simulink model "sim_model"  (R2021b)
settings: Solver=ode45  StartTime=0.0  StopTime=timeend_sim  RelTol=1e-3  EnableMultiTasking=on
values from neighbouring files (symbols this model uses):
  sel_att = 2    [runsim_sysid.m]    (also in sim_param.m = 1)
  sel_attrate = 1    [runsim_sysid.m]    (also in sim_param.m)
  sel_dltx = 1    [runsim_sysid.m]    (also in sim_param.m; runsim_ct.m = 3)
  sel_motor_thr = 1    [runsim_sysid.m]    (also in sim_param.m)
  sel_pos = 2    [runsim_sysid.m]    (also in sim_param.m = 1)
  sel_qtcalc = 1    [sim_param.m]
  sel_vel = 2    [runsim_sysid.m]    (also in sim_param.m = 1)
  sel_x_s1 = 2    [runsim_sysid.m]    (also in sim_param.m = 1)
  sel_y_s1 = 2    [runsim_sysid.m]    (also in sim_param.m = 1)
  sel_z_s1 = 2    [runsim_sysid.m]    (also in sim_param.m = 1)
undefined symbols (not defined in the file or in its folder): ct, ct2, DiscIntNeverNeededParam, mdl
libraries: simulink x4

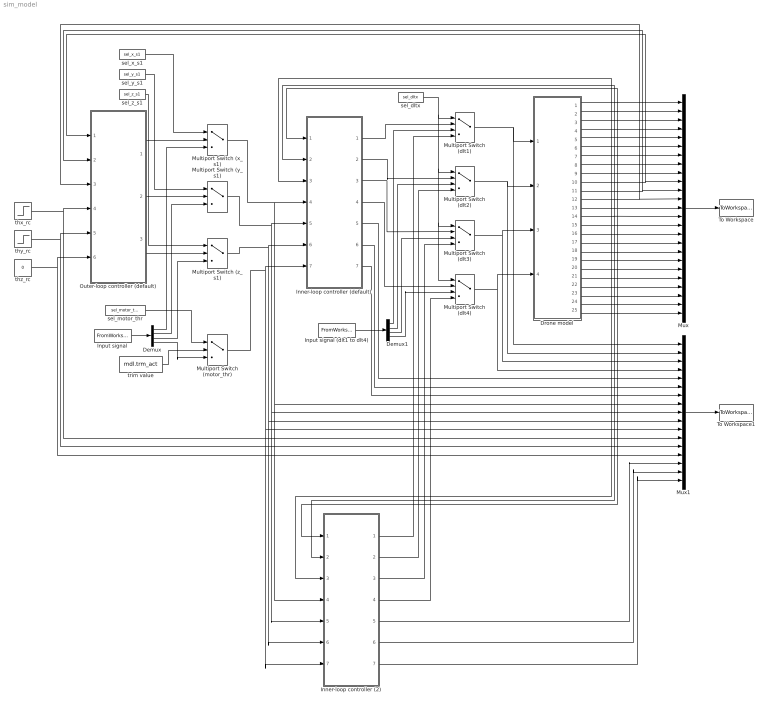
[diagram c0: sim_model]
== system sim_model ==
  Demux : Demux
  Demux1 : Demux
  Drone model : Subsystem
  Inner-loop controller (2) : Subsystem  TreatAsAtomicUnit=on  SystemSampleTime=ct2.ts_ctrl_i
  Inner-loop controller (default) : Subsystem  TreatAsAtomicUnit=on  SystemSampleTime=ct.ts_ctrl_i
  Input signal : FromWorkspace  VariableName=u_in
  Input signal (dlt1 to dlt4) : FromWorkspace  VariableName=dltx_in
  Multiport Switch (dlt1) : MultiPortSwitch
  Multiport Switch (dlt2) : MultiPortSwitch
  Multiport Switch (dlt3) : MultiPortSwitch
  Multiport Switch (dlt4) : MultiPortSwitch
  Multiport Switch (motor_thr) : MultiPortSwitch  Inputs=2
  Multiport Switch (x_s1) : MultiPortSwitch  Inputs=2
  Multiport Switch (y_s1) : MultiPortSwitch  Inputs=2
  Multiport Switch (z_s1) : MultiPortSwitch  Inputs=2
  Mux : Mux  Inputs=25
  Mux1 : Mux  Inputs=17
  Outer-loop controller (default) : Subsystem  TreatAsAtomicUnit=on  SystemSampleTime=ct.ts_ctrl_o
  To Workspace : ToWorkspace  VariableName=state_out  SaveFormat=Structure With Time  SampleTime=ct.ts_ctrl_i
  To Workspace1 : ToWorkspace  VariableName=ctrl_out  SaveFormat=Structure With Time  SampleTime=ct.ts_ctrl_i
  sel_dltx : Constant  Value=sel_dltx
  sel_motor_thr : Constant  Value=sel_motor_thr
  sel_x_s1 : Constant  Value=sel_x_s1
  sel_y_s1 : Constant  Value=sel_y_s1
  sel_z_s1 : Constant  Value=sel_z_s1
  thx_rc : Step  After=0.2  SampleTime=0
  thy_rc : Step  Time=3  After=-0.2  SampleTime=0
  thz_rc : Constant  Value=0
  trim value : Constant  Value=mdl.trm_act
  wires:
  Drone model/15(gz) -> Inner-loop controller (2)/3(gz), Mux/15, Inner-loop controller (default)/3(gz)
  Drone model/14(gy) -> Inner-loop controller (2)/2(gy), Mux/14, Inner-loop controller (default)/2(gy)
  Drone model/13(gx) -> Inner-loop controller (2)/1(gx), Mux/13, Inner-loop controller (default)/1(gx)
  Drone model/12(thz) -> Mux/12, Outer-loop controller (default)/3(thz_ahrs)
  Drone model/11(thy) -> Mux/11, Outer-loop controller (default)/2(thy_ahrs)
  Drone model/10(thx) -> Mux/10, Outer-loop controller (default)/1(thx_ahrs)
  thx_rc/1 -> Mux1/12, Outer-loop controller (default)/4(thx_rc)
  thy_rc/1 -> Mux1/13, Outer-loop controller (default)/5(thy_rc)
  thz_rc/1 -> Mux1/14, Outer-loop controller (default)/6(thz_rc)
  Mux/1 -> To Workspace/1
  Drone model/1(PXN) -> Mux/1
  Drone model/2(PYN) -> Mux/2
  Drone model/3(PZN) -> Mux/3
  Drone model/4(VXB) -> Mux/4
  Drone model/5(VYB) -> Mux/5
  Drone model/6(VZB) -> Mux/6
  Drone model/7(VXBdot) -> Mux/7
  Drone model/8(VYBdot) -> Mux/8
  Drone model/9(VZBdot) -> Mux/9
  Drone model/21(az) -> Mux/21
  Drone model/16(gxdot) -> Mux/16
  Drone model/17(gydot) -> Mux/17
  Drone model/18(gzdot) -> Mux/18
  Drone model/19(ax) -> Mux/19
  Drone model/20(ay) -> Mux/20
  Multiport Switch (x_s1)/1 -> Inner-loop controller (default)/4(x_s1), Inner-loop controller (2)/4(x_s1), Mux1/8
  Multiport Switch (y_s1)/1 -> Inner-loop controller (default)/5(y_s1), Inner-loop controller (2)/5(y_s1), Mux1/9
  Multiport Switch (z_s1)/1 -> Inner-loop controller (default)/6(z_s1), Inner-loop controller (2)/6(z_s1), Mux1/10
  Input signal/1 -> Demux/1
  Multiport Switch (motor_thr)/1 -> Inner-loop controller (default)/7(motor_thr), Inner-loop controller (2)/7(motor_thr), Mux1/11
  Drone model/22(Za) -> Mux/22
  Drone model/23(La) -> Mux/23
  Drone model/24(Ma) -> Mux/24
  Drone model/25(Na) -> Mux/25
  Multiport Switch (dlt1)/1 -> Drone model/1(dlt1), Mux1/1
  Multiport Switch (dlt2)/1 -> Drone model/2(dlt2), Mux1/2
  Multiport Switch (dlt3)/1 -> Drone model/3(dlt3), Mux1/3
  Multiport Switch (dlt4)/1 -> Drone model/4(dlt4), Mux1/4
  sel_dltx/1 -> Multiport Switch (dlt1)/1, Multiport Switch (dlt2)/1, Multiport Switch (dlt3)/1, Multiport Switch (dlt4)/1
  Mux1/1 -> To Workspace1/1
  Inner-loop controller (default)/4(motor4_pwm) -> Multiport Switch (dlt4)/2
  Input signal (dlt1 to dlt4)/1 -> Demux1/1
  Demux1/4 -> Multiport Switch (dlt4)/3
  Demux1/3 -> Multiport Switch (dlt3)/3
  Demux1/2 -> Multiport Switch (dlt2)/3
  Demux1/1 -> Multiport Switch (dlt1)/3
  Inner-loop controller (default)/1(motor1_pwm) -> Multiport Switch (dlt1)/2
  Inner-loop controller (default)/2(motor2_pwm) -> Multiport Switch (dlt2)/2
  Inner-loop controller (default)/3(motor3_pwm) -> Multiport Switch (dlt3)/2
  Inner-loop controller (2)/1(motor1_pwm) -> Multiport Switch (dlt1)/4
  Inner-loop controller (2)/2(motor2_pwm) -> Multiport Switch (dlt2)/4
  Inner-loop controller (2)/3(motor3_pwm) -> Multiport Switch (dlt3)/4
  Inner-loop controller (2)/4(motor4_pwm) -> Multiport Switch (dlt4)/4
  sel_x_s1/1 -> Multiport Switch (x_s1)/1
  sel_y_s1/1 -> Multiport Switch (y_s1)/1
  sel_z_s1/1 -> Multiport Switch (z_s1)/1
  Outer-loop controller (default)/1(x_s1) -> Multiport Switch (x_s1)/2
  Outer-loop controller (default)/2(y_s1) -> Multiport Switch (y_s1)/2
  Outer-loop controller (default)/3(z_s1) -> Multiport Switch (z_s1)/2
  Demux/1 -> Multiport Switch (x_s1)/3
  Demux/2 -> Multiport Switch (y_s1)/3
  Demux/3 -> Multiport Switch (z_s1)/3
  sel_motor_thr/1 -> Multiport Switch (motor_thr)/1
  trim value/1 -> Multiport Switch (motor_thr)/2
  Demux/4 -> Multiport Switch (motor_thr)/3
  Inner-loop controller (default)/7(z_s2) -> Mux1/7
  Inner-loop controller (default)/6(y_s2) -> Mux1/6
  Inner-loop controller (default)/5(x_s2) -> Mux1/5
  Inner-loop controller (2)/5(x_s2) -> Mux1/15
  Inner-loop controller (2)/6(y_s2) -> Mux1/16
  Inner-loop controller (2)/7(z_s2) -> Mux1/17

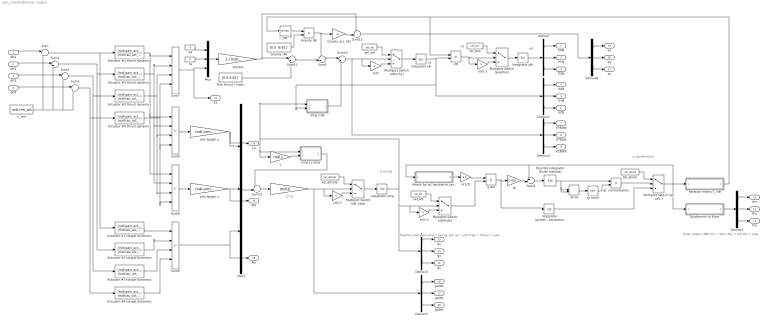
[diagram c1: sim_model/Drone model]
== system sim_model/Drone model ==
  note: Angular velocities omg = [gx gy gz]' gx = pitch gy = roll gz = yaw
  note: vN
  note: pN
  note: Euler angles (NB) thx = pitch thy = roll thz = yaw
  note: q (quaternion)
  note: vB
  note: ω (omg)
  dlt1 : Inport  PortDimensions=1
  dlt2 : Inport  Port=2  PortDimensions=1
  dlt3 : Inport  Port=3  PortDimensions=1
  dlt4 : Inport  Port=4  PortDimensions=1
  1/mass : Gain  Gain=1 / mdl.mtotal
  Actuator #1 thrust dynamics : TransferFcn  Numerator=[mdl.gain_act_t]  Denominator=[mdl.tau_act_t 1]
  Actuator #1 torque dynamics : TransferFcn  Numerator=[mdl.gain_act_r]  Denominator=[mdl.tau_act_r 1]
  Actuator #2 thrust dynamics : TransferFcn  Numerator=[mdl.gain_act_t]  Denominator=[mdl.tau_act_t 1]
  Actuator #2 torque dynamics : TransferFcn  Numerator=[mdl.gain_act_r]  Denominator=[mdl.tau_act_r 1]
  Actuator #3 thrust dynamics : TransferFcn  Numerator=[mdl.gain_act_t]  Denominator=[mdl.tau_act_t 1]
  Actuator #3 torque dynamics : TransferFcn  Numerator=[mdl.gain_act_r]  Denominator=[mdl.tau_act_r 1]
  Actuator #4 thrust dynamics : TransferFcn  Numerator=[mdl.gain_act_t]  Denominator=[mdl.tau_act_t 1]
  Actuator #4 torque dynamics : TransferFcn  Numerator=[mdl.gain_act_r]  Denominator=[mdl.tau_act_r 1]
  C_NB^T : Math  Operator=transpose  SignedPower=on
  Demux{,1..6} (7 alike) : Demux  Outputs=3
  Discrete integrator (Euler method) : UnitDelay  InitialCondition=[1 0 0 0]'  SampleTime=0.001
  Gravity (B) : Product  Multiplication=Matrix(*)  RndMeth=Zero
  Gravity (N) : Constant  Value=[0 0 -9.81]'
  Gravity acc. (B) : Gain  Gain=-1
  Integrator (quaternion) for linearization : Integrator  InitialCondition=[1 0 0 0]'
  Integrator omg : Integrator  InitialCondition=[0 0 0]'
  Integrator pN : Integrator  InitialCondition=[0 0 0]'
  Integrator vB : Integrator  InitialCondition=[0 0 0]'
  J : Gain  Gain=mdl.J  Multiplication=Matrix(K*u)
  J^-1 : Gain  Gain=mdl.Ji  Multiplication=Matrix(K*u)
  Matrix for qt. derivative calc. : Subsystem
  Multiport Switch (att. rate) : MultiPortSwitch  Inputs=2
  Multiport Switch (attitude) : MultiPortSwitch  Inputs=2
  Multiport Switch (position) : MultiPortSwitch  Inputs=2
  Multiport Switch (qt. calc.) : MultiPortSwitch  Inputs=2
  Multiport Switch (velocity) : MultiPortSwitch  Inputs=2
  Mux : Mux  Inputs=3
  Mux1 : Mux  Inputs=3
  Quaternion to Euler : Subsystem
  Rotation matrix C_NB : Subsystem
  Sum{,1..3,10} (5 alike) : Sum  Inputs=|+-
  Sum11 : Sum  Inputs=|++
  Sum12 : Sum  Inputs=++|
  Sum13 : Sum  Inputs=-+|
  Sum4 : Sum  Inputs=++|
  Sum5 : Sum  Inputs=++|
  Sum6 : Sum  Inputs=+-+-
  Sum7 : Sum  Inputs=4
  Sum8 : Sum  Inputs=-++-
  Sum9 : Sum  Inputs=--++
  Trim thrust / mass : Constant  Value=[0 0 9.81]'
  Xa : Constant  Value=0
  Ya : Constant  Value=0
  arm length x : Gain  Gain=mdl.armlenxx
  arm length y : Gain  Gain=mdl.armlenyy
  dt : Gain  Gain=0.001
  omg x J omg : Subsystem
  omg x vB : Subsystem
  q-dot : Product  Multiplication=Matrix(*)  RndMeth=Zero
  qt norm : Sqrt
  qt sq : DotProduct
  qt. normalization : Product  Inputs=*/  RndMeth=Zero
  sel_att : Constant  Value=sel_att
  sel_attrate : Constant  Value=sel_attrate
  sel_pos : Constant  Value=sel_pos
  sel_qtcalc : Constant  Value=sel_qtcalc
  sel_vel : Constant  Value=sel_vel
  u_trm : Constant  Value=mdl.trm_act
  vN : Product  Multiplication=Matrix(*)  RndMeth=Zero
  x(0) : Gain  Gain=0
  x(0) 1 : Gain  Gain=0
  x(0) 2 : Gain  Gain=0
  x(0) 3 : Gain  Gain=0
  x(1/2) : Gain  Gain=0.5
  PXN : Outport
  PYN : Outport  Port=2
  PZN : Outport  Port=3
  VXB : Outport  Port=4
  VYB : Outport  Port=5
  VZB : Outport  Port=6
  VXBdot : Outport  Port=7
  VYBdot : Outport  Port=8
  VZBdot : Outport  Port=9
  thx : Outport  Port=10
  thy : Outport  Port=11
  thz : Outport  Port=12
  gx : Outport  Port=13
  gy : Outport  Port=14
  gz : Outport  Port=15
  gxdot : Outport  Port=16
  gydot : Outport  Port=17
  gzdot : Outport  Port=18
  ax : Outport  Port=19
  ay : Outport  Port=20
  az : Outport  Port=21
  Za : Outport  Port=22
  La : Outport  Port=23
  Ma : Outport  Port=24
  Na : Outport  Port=25
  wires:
  dlt1/1 -> Sum/1
  Sum/1 -> Actuator #1 thrust dynamics/1, Actuator #1 torque dynamics/1
  dlt2/1 -> Sum1/1
  dlt3/1 -> Sum2/1
  dlt4/1 -> Sum3/1
  Sum3/1 -> Actuator #4 thrust dynamics/1, Actuator #4 torque dynamics/1
  u_trm/1 -> Sum/2, Sum1/2, Sum2/2, Sum3/2
  Actuator #1 thrust dynamics/1 -> Sum7/1, Sum8/1, Sum9/1
  Actuator #2 thrust dynamics/1 -> Sum7/2, Sum8/2, Sum9/2
  Actuator #3 thrust dynamics/1 -> Sum7/3, Sum8/3, Sum9/3
  Actuator #4 thrust dynamics/1 -> Sum7/4, Sum8/4, Sum9/4
  Sum1/1 -> Actuator #2 thrust dynamics/1, Actuator #2 torque dynamics/1
  Sum2/1 -> Actuator #3 thrust dynamics/1, Actuator #3 torque dynamics/1
  Sum9/1 -> arm length x/1
  Sum8/1 -> arm length y/1
  Actuator #1 torque dynamics/1 -> Sum6/1
  Actuator #2 torque dynamics/1 -> Sum6/2
  Actuator #3 torque dynamics/1 -> Sum6/3
  Actuator #4 torque dynamics/1 -> Sum6/4
  Sum6/1 -> Na/1, Mux1/3
  1/mass/1 -> Sum11/1, Sum12/1
  Sum10/1 -> x(0)/1, Multiport Switch (velocity)/2, Demux4/1
  Integrator vB/1 -> vN/2, omg x vB/2(U2), Demux1/1
  Mux/1 -> 1/mass/1
  Xa/1 -> Mux/1
  Ya/1 -> Mux/2
  Sum7/1 -> Mux/3, Za/1
  arm length y/1 -> Mux1/1, La/1
  arm length x/1 -> Mux1/2, Ma/1
  Gravity (N)/1 -> Gravity (B)/2
  C_NB^T/1 -> Gravity (B)/1
  Sum5/1 -> Sum10/1
  Gravity (B)/1 -> Sum5/1, Gravity acc. (B)/1
  Trim thrust / mass/1 -> Sum11/2
  Sum11/1 -> Sum5/2
  Rotation matrix C_NB/1(Rotation mat.) -> C_NB^T/1, vN/1
  Integrator pN/1 -> Demux/1
  Demux/1 -> PXN/1
  Demux/2 -> PYN/1
  Demux/3 -> PZN/1
  Demux1/1 -> VXB/1
  Demux1/2 -> VYB/1
  Demux1/3 -> VZB/1
  Demux2/1 -> thx/1
  Demux2/2 -> thy/1
  Demux2/3 -> thz/1
  Demux3/2 -> gy/1
  Demux3/3 -> gz/1
  Matrix for qt. derivative calc./1(q-times-(omg)) -> x(1/2)/1
  x(1/2)/1 -> q-dot/1
  Quaternion to Euler/1(Euler angles) -> Demux2/1
  Discrete integrator (Euler method)/1 -> qt sq/1, qt sq/2, qt. normalization/1
  qt sq/1 -> qt norm/1
  qt norm/1 -> qt. normalization/2
  Multiport Switch (qt. calc.)/1 -> Quaternion to Euler/1(Quaternion), Rotation matrix C_NB/1(Quaternion), Matrix for qt. derivative calc./1(Quaternion), Sum4/1
  Sum4/1 -> Discrete integrator (Euler method)/1
  dt/1 -> Sum4/2
  q-dot/1 -> Integrator (quaternion) for linearization/1, dt/1
  Demux4/1 -> VXBdot/1
  Demux4/2 -> VYBdot/1
  Demux4/3 -> VZBdot/1
  Demux5/1 -> gxdot/1
  Demux5/2 -> gydot/1
  Demux5/3 -> gzdot/1
  Gravity acc. (B)/1 -> Sum12/2
  Sum12/1 -> Demux6/1
  Demux6/1 -> ax/1
  Demux6/2 -> ay/1
  Demux6/3 -> az/1
  qt. normalization/1 -> Multiport Switch (qt. calc.)/2
  Integrator (quaternion) for linearization/1 -> Multiport Switch (qt. calc.)/3
  omg x vB/1(U1 x U2) -> Sum10/2
  Demux3/1 -> gx/1
  Multiport Switch (velocity)/1 -> Integrator vB/1
  sel_vel/1 -> Multiport Switch (velocity)/1
  x(0)/1 -> Multiport Switch (velocity)/3
  sel_pos/1 -> Multiport Switch (position)/1
  Multiport Switch (position)/1 -> Integrator pN/1
  vN/1 -> x(0) 1/1, Multiport Switch (position)/2
  x(0) 1/1 -> Multiport Switch (position)/3
  sel_attrate/1 -> Multiport Switch (att. rate)/1
  J^-1/1 -> x(0) 2/1, Multiport Switch (att. rate)/2, Demux5/1
  x(0) 2/1 -> Multiport Switch (att. rate)/3
  Multiport Switch (att. rate)/1 -> Integrator omg/1
  sel_att/1 -> Multiport Switch (attitude)/1
  Integrator omg/1 -> x(0) 3/1, Multiport Switch (attitude)/2, Demux3/1, J/1, omg x J omg/1(U1), omg x vB/1(U1)
  x(0) 3/1 -> Multiport Switch (attitude)/3
  Multiport Switch (attitude)/1 -> q-dot/2
  sel_qtcalc/1 -> Multiport Switch (qt. calc.)/1
  J/1 -> omg x J omg/2(U2)
  Sum13/1 -> J^-1/1
  Mux1/1 -> Sum13/2
  omg x J omg/1(U1 x U2) -> Sum13/1

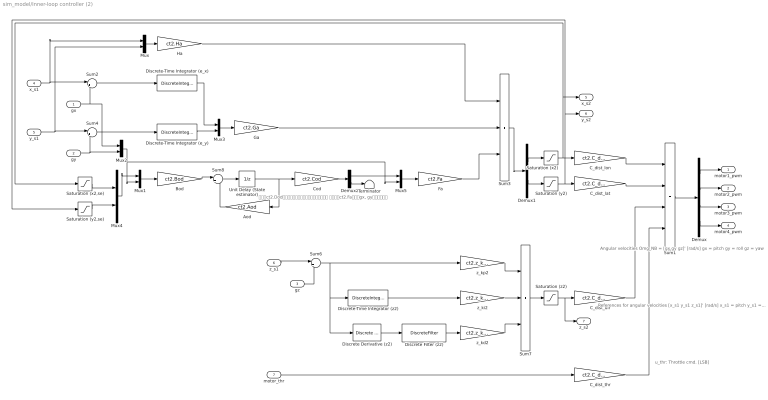
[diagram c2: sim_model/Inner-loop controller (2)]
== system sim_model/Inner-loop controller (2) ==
  note: u_thr: Throttle cmd. [LSB]
  note: References for angular velocities [x_s1 y_s1 z_s1]' [rad/s] x_s1 = pitch y_s1 = roll z_s1 = yaw
  note: Angular velocities Omg_NB = [gx gy gz]' [rad/s] gx = pitch gy = roll gz = yaw
  note: 注意：ct2.Dodを使うと代数ループの警告が出るので、 代わりにct2.Faへ直接gx, gyを入力する。
  gx : Inport  PortDimensions=1
  gy : Inport  Port=2  PortDimensions=1
  gz : Inport  Port=3  PortDimensions=1
  x_s1 : Inport  Port=4  PortDimensions=1
  y_s1 : Inport  Port=5  PortDimensions=1
  z_s1 : Inport  Port=6  PortDimensions=1
  motor_thr : Inport  Port=7  PortDimensions=1
  Aod : Gain  Gain=ct2.Aod  Multiplication=Matrix(K*u)
  Bod : Gain  Gain=ct2.Bod  Multiplication=Matrix(K*u)
  C_dist_dir : Gain  Gain=ct2.C_dist_dir  Multiplication=Matrix(K*u)
  C_dist_lat : Gain  Gain=ct2.C_dist_lat  Multiplication=Matrix(K*u)
  C_dist_lon : Gain  Gain=ct2.C_dist_lon  Multiplication=Matrix(K*u)
  C_dist_thr : Gain  Gain=ct2.C_dist_thr  Multiplication=Matrix(K*u)
  Cod : Gain  Gain=ct2.Cod  Multiplication=Matrix(K*u)
  Demux : Demux
  Demux1 : Demux  Outputs=2
  Demux2 : Demux  Outputs=[2 2]
  Discrete Derivative (z2) : simulink/Discrete/Discrete Derivative  gainval=1.0  ICPrevScaledInput=0.0  OutMin=[]  OutMax=[]  OutDataType=sfix(16)  OutScaling=2^-10  DoSatur=off
  Discrete Filter (z2) : DiscreteFilter  Numerator=[ct2.coef_dflt 0]  Denominator=[1 (ct2.coef_dflt - 1)]
  Discrete-Time Integrator (e_x) : DiscreteIntegrator  SampleTime=-1  LimitOutput=on  UpperSaturationLimit=20  LowerSaturationLimit=-20  ICPrevOutput=DiscIntNeverNeededParam  ICPrevScaledInput=DiscIntNeverNeededParam
  Discrete-Time Integrator (e_y) : DiscreteIntegrator  SampleTime=-1  LimitOutput=on  UpperSaturationLimit=20  LowerSaturationLimit=-20  ICPrevOutput=DiscIntNeverNeededParam  ICPrevScaledInput=DiscIntNeverNeededParam
  Discrete-Time Integrator (z2) : DiscreteIntegrator  SampleTime=-1  LimitOutput=on  UpperSaturationLimit=2  LowerSaturationLimit=-2  ICPrevOutput=DiscIntNeverNeededParam  ICPrevScaledInput=DiscIntNeverNeededParam
  Fa : Gain  Gain=ct2.Fa  Multiplication=Matrix(K*u)
  Ga : Gain  Gain=ct2.Ga  Multiplication=Matrix(K*u)
  Ha : Gain  Gain=ct2.Ha  Multiplication=Matrix(K*u)
  Mux{,1..5} (6 alike) : Mux  Inputs=2
  Saturation (x2) : Saturate  UpperLimit=800  LowerLimit=-800
  Saturation (x2,se) : Saturate  UpperLimit=60  LowerLimit=-60
  Saturation (y2) : Saturate  UpperLimit=800  LowerLimit=-800
  Saturation (y2,se) : Saturate  UpperLimit=60  LowerLimit=-60
  Saturation (z2) : Saturate  UpperLimit=800  LowerLimit=-800
  Sum1 : Sum  Inputs=4
  Sum2 : Sum  Inputs=|+-
  Sum3 : Sum  Inputs=3
  Sum4 : Sum  Inputs=|+-
  Sum6 : Sum  Inputs=|+-
  Sum7 : Sum  Inputs=3
  Sum8 : Sum  Inputs=|++
  Terminator : Terminator
  Unit Delay (State estimator) : UnitDelay  SampleTime=-1
  z_kd2 : Gain  Gain=ct2.z_kd2
  z_ki2 : Gain  Gain=ct2.z_ki2
  z_kp2 : Gain  Gain=ct2.z_kp2
  motor1_pwm : Outport
  motor2_pwm : Outport  Port=2
  motor3_pwm : Outport  Port=3
  motor4_pwm : Outport  Port=4
  x_s2 : Outport  Port=5
  y_s2 : Outport  Port=6
  z_s2 : Outport  Port=7
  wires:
  C_dist_thr/1 -> Sum1/4
  motor_thr/1 -> C_dist_thr/1
  Demux/4 -> motor4_pwm/1
  Demux/3 -> motor3_pwm/1
  Demux/2 -> motor2_pwm/1
  Demux/1 -> motor1_pwm/1
  Sum1/1 -> Demux/1
  C_dist_dir/1 -> Sum1/3
  gz/1 -> Sum6/2
  Discrete Derivative (z2)/1 -> Discrete Filter (z2)/1
  Sum6/1 -> z_kp2/1, Discrete-Time Integrator (z2)/1, Discrete Derivative (z2)/1
  z_s1/1 -> Sum6/1
  C_dist_lon/1 -> Sum1/1
  gx/1 -> Sum2/2, Mux2/1
  x_s1/1 -> Sum2/1, Mux/1
  C_dist_lat/1 -> Sum1/2
  gy/1 -> Sum4/2, Mux2/2
  y_s1/1 -> Sum4/1, Mux/2
  Mux/1 -> Ha/1
  Unit Delay (State estimator)/1 -> Cod/1, Aod/1
  Sum8/1 -> Unit Delay (State estimator)/1
  Aod/1 -> Sum8/2
  Sum2/1 -> Discrete-Time Integrator (e_x)/1
  Sum4/1 -> Discrete-Time Integrator (e_y)/1
  Discrete-Time Integrator (e_x)/1 -> Mux3/1
  Discrete-Time Integrator (e_y)/1 -> Mux3/2
  Mux3/1 -> Ga/1
  Fa/1 -> Sum3/3
  Ga/1 -> Sum3/2
  Ha/1 -> Sum3/1
  Sum3/1 -> Demux1/1
  Bod/1 -> Sum8/1
  Demux1/2 -> Saturation (y2)/1
  Saturation (y2)/1 -> C_dist_lat/1, Saturation (y2,se)/1, y_s2/1
  Sum7/1 -> Saturation (z2)/1
  Saturation (z2)/1 -> z_s2/1, C_dist_dir/1
  Saturation (x2)/1 -> C_dist_lon/1, Saturation (x2,se)/1, x_s2/1
  Demux1/1 -> Saturation (x2)/1
  z_kp2/1 -> Sum7/1
  z_ki2/1 -> Sum7/2
  z_kd2/1 -> Sum7/3
  Discrete-Time Integrator (z2)/1 -> z_ki2/1
  Discrete Filter (z2)/1 -> z_kd2/1
  Mux1/1 -> Bod/1
  Cod/1 -> Demux2/1
  Mux5/1 -> Fa/1
  Demux2/2 -> Terminator/1
  Demux2/1 -> Mux5/1
  Mux2/1 -> Mux5/2, Mux1/2
  Saturation (x2,se)/1 -> Mux4/1
  Saturation (y2,se)/1 -> Mux4/2
  Mux4/1 -> Mux1/1

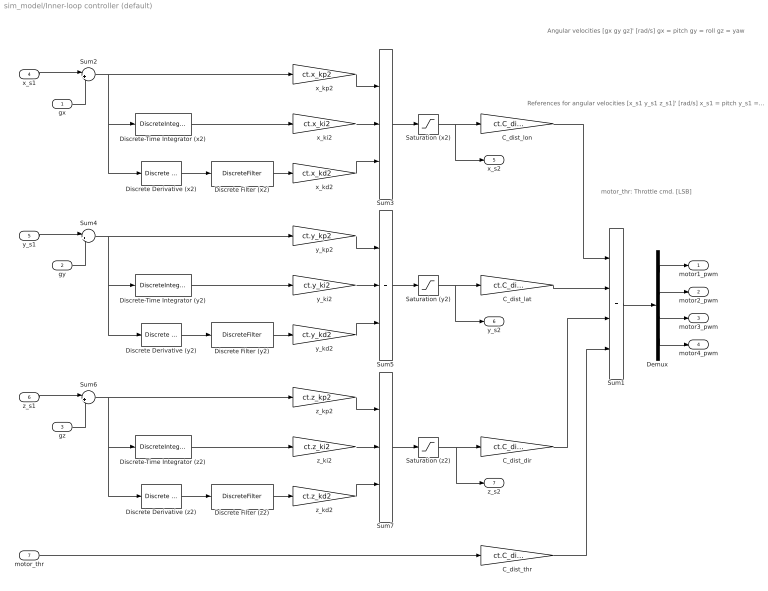
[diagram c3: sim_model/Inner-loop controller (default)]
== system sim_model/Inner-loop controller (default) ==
  note: Angular velocities [gx gy gz]' [rad/s] gx = pitch gy = roll gz = yaw
  note: References for angular velocities [x_s1 y_s1 z_s1]' [rad/s] x_s1 = pitch y_s1 = roll z_s1 = yaw
  note: motor_thr: Throttle cmd. [LSB]
  gx : Inport  PortDimensions=1
  gy : Inport  Port=2  PortDimensions=1
  gz : Inport  Port=3  PortDimensions=1
  x_s1 : Inport  Port=4  PortDimensions=1
  y_s1 : Inport  Port=5  PortDimensions=1
  z_s1 : Inport  Port=6  PortDimensions=1
  motor_thr : Inport  Port=7  PortDimensions=1
  C_dist_dir : Gain  Gain=ct.C_dist_dir  Multiplication=Matrix(K*u)
  C_dist_lat : Gain  Gain=ct.C_dist_lat  Multiplication=Matrix(K*u)
  C_dist_lon : Gain  Gain=ct.C_dist_lon  Multiplication=Matrix(K*u)
  C_dist_thr : Gain  Gain=ct.C_dist_thr  Multiplication=Matrix(K*u)
  Demux : Demux
  Discrete Derivative (x2) : simulink/Discrete/Discrete Derivative  gainval=1.0  ICPrevScaledInput=0.0  OutMin=[]  OutMax=[]  OutDataType=sfix(16)  OutScaling=2^-10  DoSatur=off
  Discrete Derivative (y2) : simulink/Discrete/Discrete Derivative  gainval=1.0  ICPrevScaledInput=0.0  OutMin=[]  OutMax=[]  OutDataType=sfix(16)  OutScaling=2^-10  DoSatur=off
  Discrete Derivative (z2) : simulink/Discrete/Discrete Derivative  gainval=1.0  ICPrevScaledInput=0.0  OutMin=[]  OutMax=[]  OutDataType=sfix(16)  OutScaling=2^-10  DoSatur=off
  Discrete Filter (x2) : DiscreteFilter  Numerator=[ct.coef_dflt 0]  Denominator=[1 (ct.coef_dflt - 1)]
  Discrete Filter (y2) : DiscreteFilter  Numerator=[ct.coef_dflt 0]  Denominator=[1 (ct.coef_dflt - 1)]
  Discrete Filter (z2) : DiscreteFilter  Numerator=[ct.coef_dflt 0]  Denominator=[1 (ct.coef_dflt - 1)]
  Discrete-Time Integrator (x2) : DiscreteIntegrator  SampleTime=-1  LimitOutput=on  UpperSaturationLimit=20  LowerSaturationLimit=-20  ICPrevOutput=DiscIntNeverNeededParam  ICPrevScaledInput=DiscIntNeverNeededParam
  Discrete-Time Integrator (y2) : DiscreteIntegrator  SampleTime=-1  LimitOutput=on  UpperSaturationLimit=20  LowerSaturationLimit=-20  ICPrevOutput=DiscIntNeverNeededParam  ICPrevScaledInput=DiscIntNeverNeededParam
  Discrete-Time Integrator (z2) : DiscreteIntegrator  SampleTime=-1  LimitOutput=on  UpperSaturationLimit=2  LowerSaturationLimit=-2  ICPrevOutput=DiscIntNeverNeededParam  ICPrevScaledInput=DiscIntNeverNeededParam
  Saturation (x2) : Saturate  UpperLimit=800  LowerLimit=-800
  Saturation (y2) : Saturate  UpperLimit=800  LowerLimit=-800
  Saturation (z2) : Saturate  UpperLimit=800  LowerLimit=-800
  Sum1 : Sum  Inputs=4
  Sum2 : Sum  Inputs=|+-
  Sum3 : Sum  Inputs=3
  Sum4 : Sum  Inputs=|+-
  Sum5 : Sum  Inputs=3
  Sum6 : Sum  Inputs=|+-
  Sum7 : Sum  Inputs=3
  x_kd2 : Gain  Gain=ct.x_kd2
  x_ki2 : Gain  Gain=ct.x_ki2
  x_kp2 : Gain  Gain=ct.x_kp2
  y_kd2 : Gain  Gain=ct.y_kd2
  y_ki2 : Gain  Gain=ct.y_ki2
  y_kp2 : Gain  Gain=ct.y_kp2
  z_kd2 : Gain  Gain=ct.z_kd2
  z_ki2 : Gain  Gain=ct.z_ki2
  z_kp2 : Gain  Gain=ct.z_kp2
  motor1_pwm : Outport
  motor2_pwm : Outport  Port=2
  motor3_pwm : Outport  Port=3
  motor4_pwm : Outport  Port=4
  x_s2 : Outport  Port=5
  y_s2 : Outport  Port=6
  z_s2 : Outport  Port=7
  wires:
  y_s1/1 -> Sum4/1
  Sum4/1 -> y_kp2/1, Discrete-Time Integrator (y2)/1, Discrete Derivative (y2)/1
  Discrete Derivative (y2)/1 -> Discrete Filter (y2)/1
  gy/1 -> Sum4/2
  C_dist_lat/1 -> Sum1/2
  x_s1/1 -> Sum2/1
  Sum2/1 -> Discrete-Time Integrator (x2)/1, Discrete Derivative (x2)/1, x_kp2/1
  x_kp2/1 -> Sum3/1
  gx/1 -> Sum2/2
  C_dist_lon/1 -> Sum1/1
  z_s1/1 -> Sum6/1
  Sum6/1 -> Discrete-Time Integrator (z2)/1, Discrete Derivative (z2)/1, z_kp2/1
  Discrete Derivative (z2)/1 -> Discrete Filter (z2)/1
  gz/1 -> Sum6/2
  C_dist_dir/1 -> Sum1/3
  Sum1/1 -> Demux/1
  Demux/1 -> motor1_pwm/1
  Demux/2 -> motor2_pwm/1
  Demux/3 -> motor3_pwm/1
  Demux/4 -> motor4_pwm/1
  motor_thr/1 -> C_dist_thr/1
  C_dist_thr/1 -> Sum1/4
  Sum3/1 -> Saturation (x2)/1
  Saturation (x2)/1 -> C_dist_lon/1, x_s2/1
  Saturation (z2)/1 -> C_dist_dir/1, z_s2/1
  Discrete Derivative (x2)/1 -> Discrete Filter (x2)/1
  Discrete-Time Integrator (x2)/1 -> x_ki2/1
  x_ki2/1 -> Sum3/2
  Discrete Filter (x2)/1 -> x_kd2/1
  x_kd2/1 -> Sum3/3
  y_kp2/1 -> Sum5/1
  Discrete-Time Integrator (y2)/1 -> y_ki2/1
  y_ki2/1 -> Sum5/2
  Discrete Filter (y2)/1 -> y_kd2/1
  y_kd2/1 -> Sum5/3
  z_kp2/1 -> Sum7/1
  Discrete-Time Integrator (z2)/1 -> z_ki2/1
  z_ki2/1 -> Sum7/2
  Discrete Filter (z2)/1 -> z_kd2/1
  z_kd2/1 -> Sum7/3
  Sum5/1 -> Saturation (y2)/1
  Sum7/1 -> Saturation (z2)/1
  Saturation (y2)/1 -> C_dist_lat/1, y_s2/1

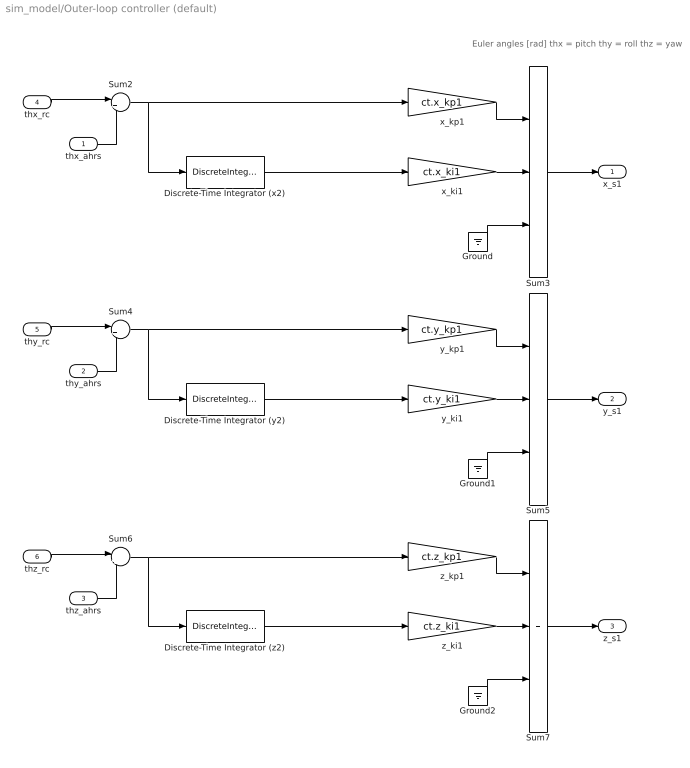
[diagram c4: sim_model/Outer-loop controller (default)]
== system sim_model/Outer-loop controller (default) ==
  note: Euler angles [rad] thx = pitch thy = roll thz = yaw
  thx_ahrs : Inport  PortDimensions=1
  thy_ahrs : Inport  Port=2  PortDimensions=1
  thz_ahrs : Inport  Port=3  PortDimensions=1
  thx_rc : Inport  Port=4  PortDimensions=1
  thy_rc : Inport  Port=5  PortDimensions=1
  thz_rc : Inport  Port=6  PortDimensions=1
  Discrete-Time Integrator (x2) : DiscreteIntegrator  SampleTime=-1  LimitOutput=on  UpperSaturationLimit=2  LowerSaturationLimit=-2  ICPrevOutput=DiscIntNeverNeededParam  ICPrevScaledInput=DiscIntNeverNeededParam
  Discrete-Time Integrator (y2) : DiscreteIntegrator  SampleTime=-1  LimitOutput=on  UpperSaturationLimit=2  LowerSaturationLimit=-2  ICPrevOutput=DiscIntNeverNeededParam  ICPrevScaledInput=DiscIntNeverNeededParam
  Discrete-Time Integrator (z2) : DiscreteIntegrator  SampleTime=-1  LimitOutput=on  UpperSaturationLimit=2  LowerSaturationLimit=-2  ICPrevOutput=DiscIntNeverNeededParam  ICPrevScaledInput=DiscIntNeverNeededParam
  Ground : Ground
  Ground1 : Ground
  Ground2 : Ground
  Sum2 : Sum  Inputs=|+-
  Sum3 : Sum  Inputs=3
  Sum4 : Sum  Inputs=|+-
  Sum5 : Sum  Inputs=3
  Sum6 : Sum  Inputs=|+-
  Sum7 : Sum  Inputs=3
  x_ki1 : Gain  Gain=ct.x_ki1
  x_kp1 : Gain  Gain=ct.x_kp1
  y_ki1 : Gain  Gain=ct.y_ki1
  y_kp1 : Gain  Gain=ct.y_kp1
  z_ki1 : Gain  Gain=ct.z_ki1
  z_kp1 : Gain  Gain=ct.z_kp1
  x_s1 : Outport
  y_s1 : Outport  Port=2
  z_s1 : Outport  Port=3
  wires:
  thz_ahrs/1 -> Sum6/2
  Ground2/1 -> Sum7/3
  z_kp1/1 -> Sum7/1
  Sum6/1 -> z_kp1/1, Discrete-Time Integrator (z2)/1
  thz_rc/1 -> Sum6/1
  thx_ahrs/1 -> Sum2/2
  x_kp1/1 -> Sum3/1
  Sum2/1 -> x_kp1/1, Discrete-Time Integrator (x2)/1
  thx_rc/1 -> Sum2/1
  thy_ahrs/1 -> Sum4/2
  Ground1/1 -> Sum5/3
  y_kp1/1 -> Sum5/1
  Sum4/1 -> y_kp1/1, Discrete-Time Integrator (y2)/1
  thy_rc/1 -> Sum4/1
  Ground/1 -> Sum3/3
  Sum5/1 -> y_s1/1
  Sum3/1 -> x_s1/1
  Sum7/1 -> z_s1/1
  Discrete-Time Integrator (x2)/1 -> x_ki1/1
  x_ki1/1 -> Sum3/2
  Discrete-Time Integrator (y2)/1 -> y_ki1/1
  y_ki1/1 -> Sum5/2
  Discrete-Time Integrator (z2)/1 -> z_ki1/1
  z_ki1/1 -> Sum7/2

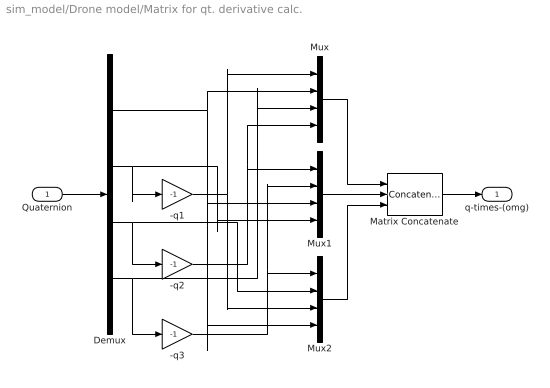
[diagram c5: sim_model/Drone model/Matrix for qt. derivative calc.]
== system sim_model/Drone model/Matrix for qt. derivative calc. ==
  Quaternion : Inport
  -q1 : Gain  Gain=-1
  -q2 : Gain  Gain=-1
  -q3 : Gain  Gain=-1
  Demux : Demux
  Matrix Concatenate : Concatenate  NumInputs=3  Mode=Multidimensional array  ConcatenateDimension=2
  Mux : Mux
  Mux1 : Mux
  Mux2 : Mux
  q-times-(omg) : Outport
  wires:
  Quaternion/1 -> Demux/1
  Demux/2 -> -q1/1, Mux1/4
  Demux/3 -> -q2/1, Mux2/2
  Demux/4 -> -q3/1, Mux/3
  -q1/1 -> Mux/1, Mux2/3
  Demux/1 -> Mux/2, Mux1/3, Mux2/4
  -q2/1 -> Mux/4, Mux1/1
  -q3/1 -> Mux1/2, Mux2/1
  Mux1/1 -> Matrix Concatenate/2
  Mux/1 -> Matrix Concatenate/1
  Mux2/1 -> Matrix Concatenate/3
  Matrix Concatenate/1 -> q-times-(omg)/1

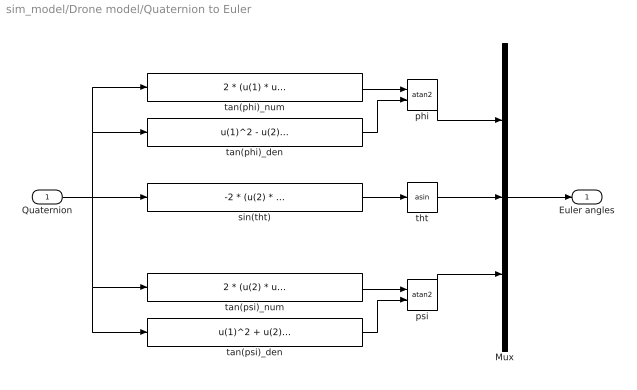
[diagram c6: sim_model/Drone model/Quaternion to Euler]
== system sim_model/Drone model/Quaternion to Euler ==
  Quaternion : Inport  PortDimensions=4
  Mux : Mux  Inputs=3
  phi : Trigonometry  Operator=atan2
  psi : Trigonometry  Operator=atan2
  sin(tht) : Fcn  Expr=-2 * (u(2) * u(4) - u(1) * u(3))
  tan(phi)_den : Fcn  Expr=u(1)^2 - u(2)^2 - u(3)^2 + u(4)^2
  tan(phi)_num : Fcn  Expr=2 * (u(1) * u(2) + u(3) * u(4))
  tan(psi)_den : Fcn  Expr=u(1)^2 + u(2)^2 - u(3)^2 - u(4)^2
  tan(psi)_num : Fcn  Expr=2 * (u(2) * u(3) + u(4) * u(1))
  tht : Trigonometry  Operator=asin
  Euler angles : Outport
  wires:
  sin(tht)/1 -> tht/1
  tan(phi)_num/1 -> phi/1
  tan(phi)_den/1 -> phi/2
  tan(psi)_num/1 -> psi/1
  tan(psi)_den/1 -> psi/2
  phi/1 -> Mux/1
  tht/1 -> Mux/2
  psi/1 -> Mux/3
  Quaternion/1 -> sin(tht)/1, tan(phi)_den/1, tan(phi)_num/1, tan(psi)_num/1, tan(psi)_den/1
  Mux/1 -> Euler angles/1

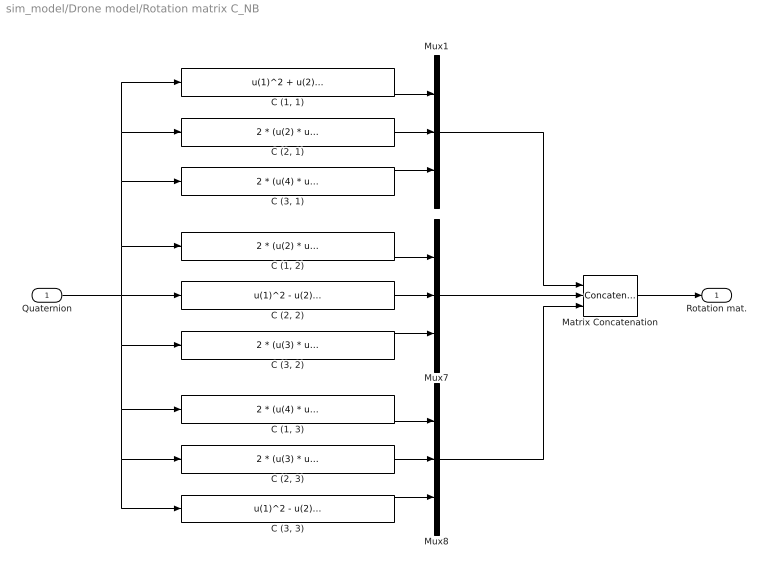
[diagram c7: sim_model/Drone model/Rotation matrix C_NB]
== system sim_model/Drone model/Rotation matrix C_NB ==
  Quaternion : Inport  PortDimensions=4
  "C (1, 1)" : Fcn  Expr=u(1)^2 + u(2)^2 - u(3)^2 - u(4)^2
  "C (1, 2)" : Fcn  Expr=2 * (u(2) * u(3) - u(4) * u(1))
  "C (1, 3)" : Fcn  Expr=2 * (u(4) * u(2) + u(3) * u(1))
  "C (2, 1)" : Fcn  Expr=2 * (u(2) * u(3) + u(4) * u(1))
  "C (2, 2)" : Fcn  Expr=u(1)^2 - u(2)^2 + u(3)^2 - u(4)^2
  "C (2, 3)" : Fcn  Expr=2 * (u(3) * u(4) - u(2) * u(1))
  "C (3, 1)" : Fcn  Expr=2 * (u(4) * u(2) - u(3) * u(1))
  "C (3, 2)" : Fcn  Expr=2 * (u(3) * u(4) + u(2) * u(1))
  "C (3, 3)" : Fcn  Expr=u(1)^2 - u(2)^2 - u(3)^2 + u(4)^2
  Matrix Concatenation : Concatenate  NumInputs=3  Mode=Multidimensional array  ConcatenateDimension=2
  Mux1 : Mux  Inputs=3
  Mux7 : Mux  Inputs=3
  Mux8 : Mux  Inputs=3
  Rotation mat. : Outport
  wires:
  Quaternion/1 -> "C (2, 2)"/1, "C (1, 1)"/1, "C (2, 1)"/1, "C (3, 1)"/1, "C (1, 2)"/1, "C (3, 2)"/1, "C (1, 3)"/1, "C (3, 3)"/1, "C (2, 3)"/1
  Matrix Concatenation/1 -> Rotation mat./1
  "C (1, 1)"/1 -> Mux1/1
  "C (2, 1)"/1 -> Mux1/2
  "C (3, 1)"/1 -> Mux1/3
  "C (1, 2)"/1 -> Mux7/1
  "C (2, 2)"/1 -> Mux7/2
  "C (3, 2)"/1 -> Mux7/3
  "C (1, 3)"/1 -> Mux8/1
  "C (2, 3)"/1 -> Mux8/2
  "C (3, 3)"/1 -> Mux8/3
  Mux7/1 -> Matrix Concatenation/2
  Mux1/1 -> Matrix Concatenation/1
  Mux8/1 -> Matrix Concatenation/3

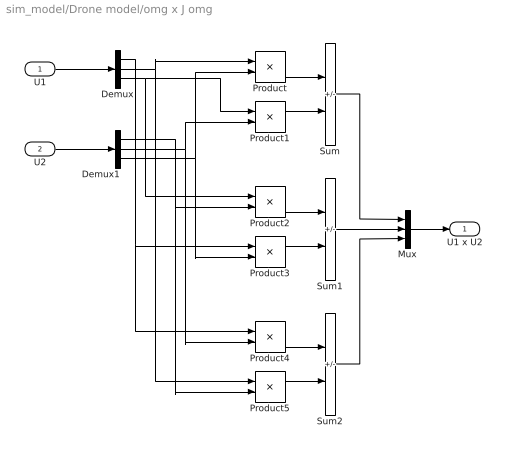
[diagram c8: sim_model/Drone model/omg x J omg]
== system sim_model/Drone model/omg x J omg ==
  U1 : Inport  PortDimensions=3
  U2 : Inport  Port=2  PortDimensions=3
  Demux : Demux  Outputs=3
  Demux1 : Demux  Outputs=3
  Mux : Mux  Inputs=3
  Product{,1..5} (6 alike) : Product  RndMeth=Zero
  Sum : Sum  Inputs=+-
  Sum1 : Sum  Inputs=+-
  Sum2 : Sum  Inputs=+-
  U1 x U2 : Outport
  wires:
  Sum2/1 -> Mux/3
  Sum/1 -> Mux/1
  Sum1/1 -> Mux/2
  Demux/1 -> Product4/1, Product3/1
  Demux1/1 -> Product5/2, Product2/2
  Product5/1 -> Sum2/2
  Product4/1 -> Sum2/1
  Product3/1 -> Sum1/2
  Product2/1 -> Sum1/1
  Demux1/2 -> Product4/2, Product1/2
  Demux/3 -> Product2/1, Product1/1
  Demux1/3 -> Product3/2, Product/2
  Demux/2 -> Product5/1, Product/1
  Product1/1 -> Sum/2
  Product/1 -> Sum/1
  Mux/1 -> U1 x U2/1
  U2/1 -> Demux1/1
  U1/1 -> Demux/1

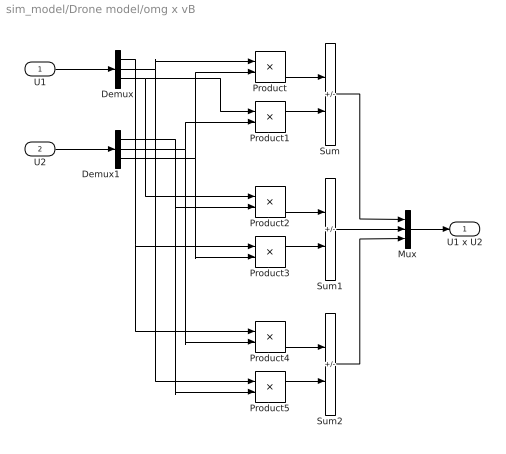
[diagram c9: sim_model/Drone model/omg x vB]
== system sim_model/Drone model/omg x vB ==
  U1 : Inport  PortDimensions=3
  U2 : Inport  Port=2  PortDimensions=3
  Demux : Demux  Outputs=3
  Demux1 : Demux  Outputs=3
  Mux : Mux  Inputs=3
  Product{,1..5} (6 alike) : Product  RndMeth=Zero
  Sum : Sum  Inputs=+-
  Sum1 : Sum  Inputs=+-
  Sum2 : Sum  Inputs=+-
  U1 x U2 : Outport
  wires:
  U1/1 -> Demux/1
  U2/1 -> Demux1/1
  Mux/1 -> U1 x U2/1
  Product/1 -> Sum/1
  Product1/1 -> Sum/2
  Demux/2 -> Product/1, Product5/1
  Demux1/3 -> Product/2, Product3/2
  Demux/3 -> Product1/1, Product2/1
  Demux1/2 -> Product1/2, Product4/2
  Product2/1 -> Sum1/1
  Product3/1 -> Sum1/2
  Product4/1 -> Sum2/1
  Product5/1 -> Sum2/2
  Demux1/1 -> Product2/2, Product5/2
  Demux/1 -> Product3/1, Product4/1
  Sum1/1 -> Mux/2
  Sum/1 -> Mux/1
  Sum2/1 -> Mux/3
